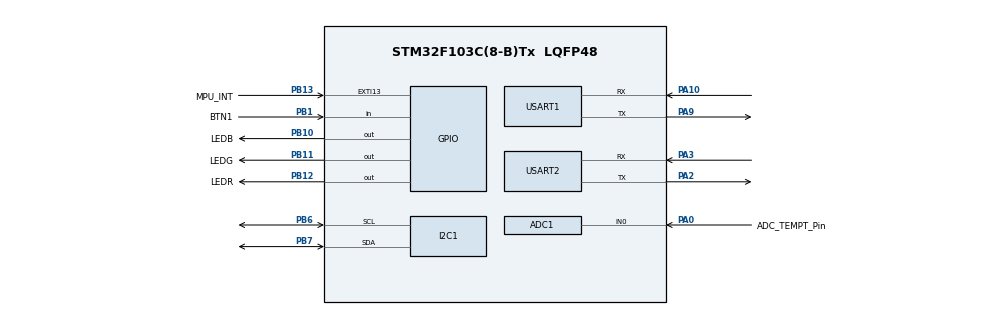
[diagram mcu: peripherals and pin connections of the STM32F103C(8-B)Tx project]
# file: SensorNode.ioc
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ADC1.Channel-2\#ChannelRegularConversion=ADC_CHANNEL_0
ADC1.NbrOfConversionFlag=1
ADC1.Rank-2\#ChannelRegularConversion=1
ADC1.SamplingTime-2\#ChannelRegularConversion=ADC_SAMPLETIME_1CYCLE_5
ADC1.master=1
Mcu.Family=STM32F1
Mcu.Name=STM32F103C(8-B)Tx
Mcu.Package=LQFP48
NVIC.PriorityGroup=NVIC_PRIORITYGROUP_4
NVIC.TIM2_IRQn=true\:0\:0\:false\:false\:true\:true\:true\:true
PA0-WKUP.GPIO_Label=ADC_TEMPT_Pin
PA0-WKUP.Signal=ADCx_IN0
PA10.Mode=Asynchronous
PA10.Signal=USART1_RX
PA2.Mode=Asynchronous
PA2.Signal=USART2_TX
PA3.Mode=Asynchronous
PA3.Signal=USART2_RX
PA9.Mode=Asynchronous
PA9.Signal=USART1_TX
PB1.GPIO_Label=BTN1
PB1.Signal=GPIO_Input
PB10.GPIO_Label=LEDB
PB10.PinState=GPIO_PIN_SET
PB10.Signal=GPIO_Output
PB11.GPIO_Label=LEDG
PB11.PinState=GPIO_PIN_SET
PB11.Signal=GPIO_Output
PB12.GPIO_Label=LEDR
PB12.PinState=GPIO_PIN_SET
PB12.Signal=GPIO_Output
PB13.GPIO_Label=MPU_INT
PB13.Signal=GPXTI13
PB6.Mode=I2C
PB6.Signal=I2C1_SCL
PB7.Mode=I2C
PB7.Signal=I2C1_SDA
ProjectManager.HeapSize=0x200
ProjectManager.StackSize=0x400
ProjectManager.TargetToolchain=STM32CubeIDE
RCC.ADCPresc=RCC_ADCPCLK2_DIV8
RCC.AHBFreq_Value=72000000
RCC.APB1CLKDivider=RCC_HCLK_DIV2
RCC.APB1Freq_Value=36000000
RCC.APB1TimFreq_Value=72000000
RCC.APB2Freq_Value=72000000
RCC.APB2TimFreq_Value=72000000
RCC.HCLKFreq_Value=72000000
RCC.PLLMUL=RCC_PLL_MUL9
RCC.PLLSourceVirtual=RCC_PLLSOURCE_HSE
RCC.SYSCLKFreq_VALUE=72000000
RCC.SYSCLKSource=RCC_SYSCLKSOURCE_PLLCLK
RCC.USBFreq_Value=72000000
SH.ADCx_IN0.0=ADC1_IN0,IN0
TIM2.Period=1999
TIM2.Prescaler=35999
USART1.VirtualMode=VM_ASYNC
USART2.VirtualMode=VM_ASYNC
VP_TIM2_VS_ClockSourceINT.Mode=Internal
board=custom

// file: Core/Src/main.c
/* USER CODE BEGIN Header */
/**
  ******************************************************************************
  * @file           : main.c
  * @brief          : Main program body
  ******************************************************************************
  * @attention
  *
  * Copyright (c) 2023 STMicroelectronics.
  * All rights reserved.
  *
  * This software is licensed under terms that can be found in the LICENSE file
  * in the root directory of this software component.
  * If no LICENSE file comes with this software, it is provided AS-IS.
  *
  ******************************************************************************
  */
/* USER CODE END Header */
#include "main.h"

/* USER CODE BEGIN Includes */
#include "stdio.h"
#include "ina219.h"
#include <stdbool.h>
#include <stdbool.h>
/* USER CODE END Includes */

/* USER CODE BEGIN PM */
//#define PUTCHAR_PROTOTYPE int __io_putchar(int ch)
/* USER CODE END PM */

ADC_HandleTypeDef hadc1;

I2C_HandleTypeDef hi2c1;

TIM_HandleTypeDef htim2;

UART_HandleTypeDef huart1;
UART_HandleTypeDef huart2;

/* USER CODE BEGIN PV */
uint32_t GetTemperature_raw(void);
uint32_t GetTemperature(void);

INA219_t ina219;

int16_t uvbus, uvshunt, ucurrent, upower;

bool isPrint = false;

bool isPrint = false;
/* USER CODE END PV */

void SystemClock_Config(void);
static void MX_GPIO_Init(void);
static void MX_ADC1_Init(void);
static void MX_I2C1_Init(void);
static void MX_USART1_UART_Init(void);
static void MX_USART2_UART_Init(void);
static void MX_TIM2_Init(void);
static void MX_TIM2_Init(void);
/* USER CODE BEGIN PFP */
void HAL_TIM_PeriodElapsedCallback(TIM_HandleTypeDef *htim)
{
 if(htim->Instance == htim2.Instance)
 {
   HAL_GPIO_TogglePin(GPIOB, LEDG_Pin);
   isPrint = true;
 }
}
void HAL_TIM_PeriodElapsedCallback(TIM_HandleTypeDef *htim)
{
 if(htim->Instance == htim2.Instance)
 {
   HAL_GPIO_TogglePin(GPIOB, LEDG_Pin);
   isPrint = true;
 }
}
/* USER CODE END PFP */

int main(void)
{

  /* MCU Configuration--------------------------------------------------------*/

  /* Reset of all peripherals, Initializes the Flash interface and the Systick. */
  HAL_Init();

  /* Configure the system clock */
  SystemClock_Config();

  /* Initialize all configured peripherals */
  MX_GPIO_Init();
  MX_ADC1_Init();
  MX_I2C1_Init();
  MX_USART1_UART_Init();
  MX_USART2_UART_Init();
  MX_TIM2_Init();
  MX_TIM2_Init();
  /* USER CODE BEGIN 2 */
  while(!INA219_Init(&ina219, &hi2c1, INA219_ADDRESS))
  {
	  HAL_GPIO_WritePin(GPIOB, LEDR_Pin, GPIO_PIN_RESET); // on LedRed
  }
  HAL_GPIO_WritePin(GPIOB, LEDR_Pin, GPIO_PIN_SET); 	// off LedRed
  HAL_TIM_Base_Start_IT(&htim2);

  uvbus = INA219_ReadBusVoltage_mV(&ina219);
  uvshunt = INA219_ReadShuntVolage_mV(&ina219);
  ucurrent = INA219_ReadCurrent_mA(&ina219);
  upower = INA219_ReadPower_mW(&ina219);
  /* USER CODE END 2 */

  /* Infinite loop */
  while (1)
  {

    /* USER CODE BEGIN 3 */
	  uint32_t temp = GetTemperature();

	  if(isPrint)
	  {
		  printf("Vb: %.02u mV\n", uvbus);
		  printf("Vs: %.02u mV\n", uvshunt);
		  printf("\nC: %.02u mA\n", ucurrent);
		  printf("P: %.02u mW\n", upower);

		  printf("T: %ld.%02ld\n", temp / 100, temp % 100);
		  isPrint = false;
	  }
  }
  /* USER CODE END 3 */
}

void SystemClock_Config(void)
{
  RCC_OscInitTypeDef RCC_OscInitStruct = {0};
  RCC_ClkInitTypeDef RCC_ClkInitStruct = {0};
  RCC_PeriphCLKInitTypeDef PeriphClkInit = {0};

  /** Initializes the RCC Oscillators according to the specified parameters
  * in the RCC_OscInitTypeDef structure.
  */
  RCC_OscInitStruct.OscillatorType = RCC_OSCILLATORTYPE_HSI;
  RCC_OscInitStruct.HSIState = RCC_HSI_ON;
  RCC_OscInitStruct.HSICalibrationValue = RCC_HSICALIBRATION_DEFAULT;
  RCC_OscInitStruct.PLL.PLLState = RCC_PLL_NONE;
  if (HAL_RCC_OscConfig(&RCC_OscInitStruct) != HAL_OK)
  {
    Error_Handler();
  }

  /** Initializes the CPU, AHB and APB buses clocks
  */
  RCC_ClkInitStruct.ClockType = RCC_CLOCKTYPE_HCLK|RCC_CLOCKTYPE_SYSCLK
                              |RCC_CLOCKTYPE_PCLK1|RCC_CLOCKTYPE_PCLK2;
  RCC_ClkInitStruct.SYSCLKSource = RCC_SYSCLKSOURCE_HSI;
  RCC_ClkInitStruct.AHBCLKDivider = RCC_SYSCLK_DIV1;
  RCC_ClkInitStruct.APB1CLKDivider = RCC_HCLK_DIV1;
  RCC_ClkInitStruct.APB2CLKDivider = RCC_HCLK_DIV1;

  if (HAL_RCC_ClockConfig(&RCC_ClkInitStruct, FLASH_LATENCY_0) != HAL_OK)
  {
    Error_Handler();
  }
  PeriphClkInit.PeriphClockSelection = RCC_PERIPHCLK_ADC;
  PeriphClkInit.AdcClockSelection = RCC_ADCPCLK2_DIV2;
  if (HAL_RCCEx_PeriphCLKConfig(&PeriphClkInit) != HAL_OK)
  {
    Error_Handler();
  }
}

static void MX_ADC1_Init(void)
{

  ADC_ChannelConfTypeDef sConfig = {0};

  /** Common config
  */
  hadc1.Instance = ADC1;
  hadc1.Init.ScanConvMode = ADC_SCAN_DISABLE;
  hadc1.Init.ContinuousConvMode = DISABLE;
  hadc1.Init.DiscontinuousConvMode = DISABLE;
  hadc1.Init.ExternalTrigConv = ADC_SOFTWARE_START;
  hadc1.Init.DataAlign = ADC_DATAALIGN_RIGHT;
  hadc1.Init.NbrOfConversion = 1;
  if (HAL_ADC_Init(&hadc1) != HAL_OK)
  {
    Error_Handler();
  }

  /** Configure Regular Channel
  */
  sConfig.Channel = ADC_CHANNEL_4;
  sConfig.Rank = ADC_REGULAR_RANK_1;
  sConfig.SamplingTime = ADC_SAMPLETIME_1CYCLE_5;
  if (HAL_ADC_ConfigChannel(&hadc1, &sConfig) != HAL_OK)
  {
    Error_Handler();
  }

}

static void MX_I2C1_Init(void)
{

  hi2c1.Instance = I2C1;
  hi2c1.Init.ClockSpeed = 100000;
  hi2c1.Init.DutyCycle = I2C_DUTYCYCLE_2;
  hi2c1.Init.OwnAddress1 = 0;
  hi2c1.Init.AddressingMode = I2C_ADDRESSINGMODE_7BIT;
  hi2c1.Init.DualAddressMode = I2C_DUALADDRESS_DISABLE;
  hi2c1.Init.OwnAddress2 = 0;
  hi2c1.Init.GeneralCallMode = I2C_GENERALCALL_DISABLE;
  hi2c1.Init.NoStretchMode = I2C_NOSTRETCH_DISABLE;
  if (HAL_I2C_Init(&hi2c1) != HAL_OK)
  {
    Error_Handler();
  }

}

static void MX_TIM2_Init(void)
{

  TIM_ClockConfigTypeDef sClockSourceConfig = {0};
  TIM_MasterConfigTypeDef sMasterConfig = {0};

  htim2.Instance = TIM2;
  htim2.Init.Prescaler = 35999;
  htim2.Init.CounterMode = TIM_COUNTERMODE_UP;
  htim2.Init.Period = 1999;
  htim2.Init.ClockDivision = TIM_CLOCKDIVISION_DIV1;
  htim2.Init.AutoReloadPreload = TIM_AUTORELOAD_PRELOAD_DISABLE;
  if (HAL_TIM_Base_Init(&htim2) != HAL_OK)
  {
    Error_Handler();
  }
  sClockSourceConfig.ClockSource = TIM_CLOCKSOURCE_INTERNAL;
  if (HAL_TIM_ConfigClockSource(&htim2, &sClockSourceConfig) != HAL_OK)
  {
    Error_Handler();
  }
  sMasterConfig.MasterOutputTrigger = TIM_TRGO_RESET;
  sMasterConfig.MasterSlaveMode = TIM_MASTERSLAVEMODE_DISABLE;
  if (HAL_TIMEx_MasterConfigSynchronization(&htim2, &sMasterConfig) != HAL_OK)
  {
    Error_Handler();
  }

}

static void MX_USART1_UART_Init(void)
{

  huart1.Instance = USART1;
  huart1.Init.BaudRate = 115200;
  huart1.Init.WordLength = UART_WORDLENGTH_8B;
  huart1.Init.StopBits = UART_STOPBITS_1;
  huart1.Init.Parity = UART_PARITY_NONE;
  huart1.Init.Mode = UART_MODE_TX_RX;
  huart1.Init.HwFlowCtl = UART_HWCONTROL_NONE;
  huart1.Init.OverSampling = UART_OVERSAMPLING_16;
  if (HAL_UART_Init(&huart1) != HAL_OK)
  {
    Error_Handler();
  }

}

static void MX_USART2_UART_Init(void)
{

  huart2.Instance = USART2;
  huart2.Init.BaudRate = 115200;
  huart2.Init.WordLength = UART_WORDLENGTH_8B;
  huart2.Init.StopBits = UART_STOPBITS_1;
  huart2.Init.Parity = UART_PARITY_NONE;
  huart2.Init.Mode = UART_MODE_TX_RX;
  huart2.Init.HwFlowCtl = UART_HWCONTROL_NONE;
  huart2.Init.OverSampling = UART_OVERSAMPLING_16;
  if (HAL_UART_Init(&huart2) != HAL_OK)
  {
    Error_Handler();
  }

}

static void MX_GPIO_Init(void)
{
  GPIO_InitTypeDef GPIO_InitStruct = {0};

  /* GPIO Ports Clock Enable */
  __HAL_RCC_GPIOA_CLK_ENABLE();
  __HAL_RCC_GPIOB_CLK_ENABLE();

  /*Configure GPIO pin Output Level */
  HAL_GPIO_WritePin(XSHUT_MCU1_0_GPIO_Port, XSHUT_MCU1_0_Pin, GPIO_PIN_RESET);

  /*Configure GPIO pin Output Level */
  HAL_GPIO_WritePin(GPIOB, LEDB_Pin|LEDG_Pin|LEDR_Pin, GPIO_PIN_SET);

  /*Configure GPIO pin Output Level */
  HAL_GPIO_WritePin(GPIOB, MPU_BOOT_Pin|MPU_RST_Pin|XSHUT_MCU1_1_Pin, GPIO_PIN_RESET);

  /*Configure GPIO pin Output Level */
  HAL_GPIO_WritePin(SPI_CS_GPIO_Port, SPI_CS_Pin, GPIO_PIN_RESET);

  /*Configure GPIO pin : GPIO1_MCU1_0_Pin */
  GPIO_InitStruct.Pin = GPIO1_MCU1_0_Pin;
  GPIO_InitStruct.Mode = GPIO_MODE_IT_RISING;
  GPIO_InitStruct.Pull = GPIO_NOPULL;
  HAL_GPIO_Init(GPIO1_MCU1_0_GPIO_Port, &GPIO_InitStruct);

  /*Configure GPIO pin : XSHUT_MCU1_0_Pin */
  GPIO_InitStruct.Pin = XSHUT_MCU1_0_Pin;
  GPIO_InitStruct.Mode = GPIO_MODE_OUTPUT_PP;
  GPIO_InitStruct.Pull = GPIO_NOPULL;
  GPIO_InitStruct.Speed = GPIO_SPEED_FREQ_LOW;
  HAL_GPIO_Init(XSHUT_MCU1_0_GPIO_Port, &GPIO_InitStruct);

  /*Configure GPIO pins : BTN2_Pin BTN1_Pin */
  GPIO_InitStruct.Pin = BTN2_Pin|BTN1_Pin;
  GPIO_InitStruct.Mode = GPIO_MODE_INPUT;
  GPIO_InitStruct.Pull = GPIO_NOPULL;
  HAL_GPIO_Init(BTN1_GPIO_Port, &GPIO_InitStruct);

  /*Configure GPIO pins : LEDB_Pin LEDG_Pin LEDR_Pin */
  GPIO_InitStruct.Pin = LEDB_Pin|LEDG_Pin|LEDR_Pin;
  GPIO_InitStruct.Mode = GPIO_MODE_OUTPUT_PP;
  GPIO_InitStruct.Pull = GPIO_NOPULL;
  GPIO_InitStruct.Speed = GPIO_SPEED_FREQ_LOW;
  HAL_GPIO_Init(GPIOB, &GPIO_InitStruct);

  /*Configure GPIO pin : MPU_INT_Pin */
  GPIO_InitStruct.Pin = MPU_INT_Pin;
  GPIO_InitStruct.Mode = GPIO_MODE_IT_RISING;
  GPIO_InitStruct.Pull = GPIO_NOPULL;
  HAL_GPIO_Init(MPU_INT_GPIO_Port, &GPIO_InitStruct);

}

/* USER CODE BEGIN 4 */
uint32_t GetTemperature(void)
{
	uint32_t ADC_val = GetTemperature_raw();
	uint32_t ADC_val = GetTemperature_raw();

  uint32_t temp = (ADC_val * 5 * 100) / 4095;
  uint32_t temp_decimal = ((ADC_val * 5) % 4095) * 100 / 4095;

  uint32_t temperature = temp * 100 + temp_decimal;
  return temperature;
}
uint32_t GetTemperature_raw(void)
{
	uint32_t ADC_val;

  HAL_ADC_Start(&hadc1);
  HAL_ADC_PollForConversion(&hadc1, 2000);
  ADC_val = HAL_ADC_GetValue(&hadc1);
  HAL_ADC_Stop(&hadc1);

  return ADC_val;
}

//#if defined(__GNUC__)
//int _write(int fd, char * ptr, int len) {
//  HAL_UART_Transmit( & huart1, (uint8_t * ) ptr, len, HAL_MAX_DELAY);
//  return len;
//}
//#elif defined(__ICCARM__)#include "LowLevelIOInterface.h"
//
//size_t __write(int handle,
//  const unsigned char * buffer, size_t size) {
//  HAL_UART_Transmit( & huart1, (uint8_t * ) buffer, size, HAL_MAX_DELAY);
//  return size;
//}
//#elif defined(__CC_ARM)
//int fputc(int ch, FILE * f) {
//  HAL_UART_Transmit( & huart1, (uint8_t * ) & ch, 1, HAL_MAX_DELAY);
//  return ch;
//}
//#endif

//PUTCHAR_PROTOTYPE
//{
//  /* Place your implementation of fputc here */
//  /* e.g. write a character to the USART1 and Loop until the end of transmission */
//  HAL_UART_Transmit(&huart1, (uint8_t *)&ch, 1, 0xFFFF);
//
//  return ch;
//}
/* USER CODE END 4 */

void Error_Handler(void)
{
  __disable_irq();
  while (1)
  {
  }
}
